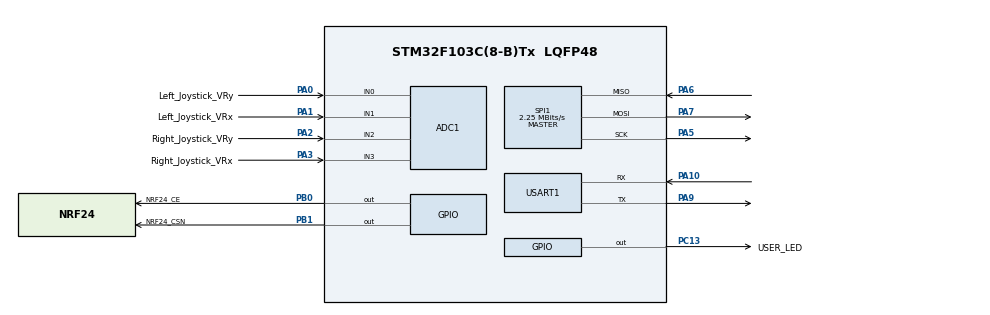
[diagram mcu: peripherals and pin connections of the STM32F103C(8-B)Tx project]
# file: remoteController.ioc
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ADC1.Channel-0\#ChannelRegularConversion=ADC_CHANNEL_0
ADC1.Channel-1\#ChannelRegularConversion=ADC_CHANNEL_1
ADC1.Channel-2\#ChannelRegularConversion=ADC_CHANNEL_2
ADC1.Channel-3\#ChannelRegularConversion=ADC_CHANNEL_3
ADC1.ContinuousConvMode=ENABLE
ADC1.NbrOfConversion=4
ADC1.NbrOfConversionFlag=1
ADC1.Rank-0\#ChannelRegularConversion=1
ADC1.Rank-1\#ChannelRegularConversion=2
ADC1.Rank-2\#ChannelRegularConversion=3
ADC1.Rank-3\#ChannelRegularConversion=4
ADC1.SamplingTime-0\#ChannelRegularConversion=ADC_SAMPLETIME_239CYCLES_5
ADC1.SamplingTime-1\#ChannelRegularConversion=ADC_SAMPLETIME_239CYCLES_5
ADC1.SamplingTime-2\#ChannelRegularConversion=ADC_SAMPLETIME_239CYCLES_5
ADC1.SamplingTime-3\#ChannelRegularConversion=ADC_SAMPLETIME_239CYCLES_5
ADC1.master=1
Dma.ADC1.0.Direction=DMA_PERIPH_TO_MEMORY
Dma.ADC1.0.Instance=DMA1_Channel1
Dma.ADC1.0.MemDataAlignment=DMA_MDATAALIGN_WORD
Dma.ADC1.0.MemInc=DMA_MINC_ENABLE
Dma.ADC1.0.Mode=DMA_CIRCULAR
Dma.ADC1.0.PeriphDataAlignment=DMA_PDATAALIGN_WORD
Dma.ADC1.0.PeriphInc=DMA_PINC_DISABLE
Dma.ADC1.0.Priority=DMA_PRIORITY_MEDIUM
Dma.Request0=ADC1
Mcu.Family=STM32F1
Mcu.Name=STM32F103C(8-B)Tx
Mcu.Package=LQFP48
NVIC.DMA1_Channel1_IRQn=true\:0\:0\:false\:false\:true\:false\:true\:true
NVIC.PriorityGroup=NVIC_PRIORITYGROUP_4
NVIC.SPI1_IRQn=true\:0\:0\:false\:false\:true\:true\:true\:true
NVIC.TIM2_IRQn=true\:0\:0\:false\:false\:true\:true\:true\:true
PA0-WKUP.GPIO_Label=Left_Joystick_VRy
PA0-WKUP.Signal=ADCx_IN0
PA1.GPIO_Label=Left_Joystick_VRx
PA1.Signal=ADCx_IN1
PA10.Mode=Asynchronous
PA10.Signal=USART1_RX
PA13.Mode=Serial_Wire
PA13.Signal=SYS_JTMS-SWDIO
PA14.Mode=Serial_Wire
PA14.Signal=SYS_JTCK-SWCLK
PA2.GPIO_Label=Right_Joystick_VRy
PA2.Signal=ADCx_IN2
PA3.GPIO_Label=Right_Joystick_VRx
PA3.Signal=ADCx_IN3
PA5.Mode=Full_Duplex_Master
PA5.Signal=SPI1_SCK
PA6.Mode=Full_Duplex_Master
PA6.Signal=SPI1_MISO
PA7.Mode=Full_Duplex_Master
PA7.Signal=SPI1_MOSI
PA9.Mode=Asynchronous
PA9.Signal=USART1_TX
PB0.GPIO_Label=NRF24_CE
PB0.GPIO_Speed=GPIO_SPEED_FREQ_HIGH
PB0.Signal=GPIO_Output
PB1.GPIO_Label=NRF24_CSN
PB1.GPIO_Speed=GPIO_SPEED_FREQ_HIGH
PB1.Signal=GPIO_Output
PC13-TAMPER-RTC.GPIO_Label=USER_LED
PC13-TAMPER-RTC.GPIO_PuPd=GPIO_PULLDOWN
PC13-TAMPER-RTC.GPIO_Speed=GPIO_SPEED_FREQ_MEDIUM
PC13-TAMPER-RTC.Signal=GPIO_Output
PD0-OSC_IN.Mode=HSE-External-Oscillator
PD0-OSC_IN.Signal=RCC_OSC_IN
PD1-OSC_OUT.Mode=HSE-External-Oscillator
PD1-OSC_OUT.Signal=RCC_OSC_OUT
ProjectManager.HeapSize=0x200
ProjectManager.StackSize=0x400
ProjectManager.TargetToolchain=STM32CubeIDE
RCC.ADCPresc=RCC_ADCPCLK2_DIV8
RCC.AHBFreq_Value=72000000
RCC.APB1CLKDivider=RCC_HCLK_DIV2
RCC.APB1Freq_Value=36000000
RCC.APB1TimFreq_Value=72000000
RCC.APB2Freq_Value=72000000
RCC.APB2TimFreq_Value=72000000
RCC.HCLKFreq_Value=72000000
RCC.PLLMUL=RCC_PLL_MUL9
RCC.PLLSourceVirtual=RCC_PLLSOURCE_HSE
RCC.SYSCLKFreq_VALUE=72000000
RCC.SYSCLKSource=RCC_SYSCLKSOURCE_PLLCLK
RCC.USBFreq_Value=72000000
SH.ADCx_IN0.0=ADC1_IN0,IN0
SH.ADCx_IN1.0=ADC1_IN1,IN1
SH.ADCx_IN2.0=ADC1_IN2,IN2
SH.ADCx_IN3.0=ADC1_IN3,IN3
SPI1.BaudRatePrescaler=SPI_BAUDRATEPRESCALER_32
SPI1.CalculateBaudRate=2.25 MBits/s
SPI1.Direction=SPI_DIRECTION_2LINES
SPI1.Mode=SPI_MODE_MASTER
SPI1.VirtualType=VM_MASTER
TIM1.Prescaler=72-1
TIM2.Period=999
TIM2.Prescaler=71
USART1.VirtualMode=VM_ASYNC
VP_TIM1_VS_ClockSourceINT.Mode=Internal
VP_TIM2_VS_ClockSourceINT.Mode=Internal
board=custom

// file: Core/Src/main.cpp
/* USER CODE BEGIN Header */
/**
  ******************************************************************************
  * @file           : main.c
  * @brief          : Main program body
  ******************************************************************************
  * @attention
  *
  * Copyright (c) 2025 STMicroelectronics.
  * All rights reserved.
  *
  * This software is licensed under terms that can be found in the LICENSE file
  * in the root directory of this software component.
  * If no LICENSE file comes with this software, it is provided AS-IS.
  *
  ******************************************************************************
  */
/* USER CODE END Header */
#include "main.h"
#include "adc.h"
#include "dma.h"
#include "spi.h"
#include "tim.h"
#include "usart.h"
#include "gpio.h"

/* USER CODE BEGIN Includes */
#include "config.h"
#include "global.h"
#include <stdio.h>
#include <string.h>
#include "softTimer.h"
#include "nrflink.h"
/* USER CODE END Includes */

/* USER CODE BEGIN PD */
uint32_t data[4];
softwareTimer timer1;

/* USER CODE END PD */

/* USER CODE BEGIN PV */
//uint8_t TxData[] = "Hello World\r\n";

uint8_t TxData[32] = {0};
/* USER CODE END PV */

void SystemClock_Config(void);

int main(void)
{

  /* MCU Configuration--------------------------------------------------------*/

  /* Reset of all peripherals, Initializes the Flash interface and the Systick. */
  HAL_Init();

  /* Configure the system clock */
  SystemClock_Config();

  /* Initialize all configured peripherals */
  MX_GPIO_Init();
  MX_DMA_Init();
  MX_ADC1_Init();
  MX_USART1_UART_Init();
  MX_SPI1_Init();
  MX_TIM2_Init();
  MX_TIM1_Init();
  /* USER CODE BEGIN 2 */
  HAL_ADC_Start_DMA(&hadc1, gu32a_adc_val, ADC_CHANNEL_NUMBERS);
  HAL_TIM_Base_Start_IT(&htim2);
  HAL_TIM_Base_Start(&htim1);  // start the Timer1

  timer1.start(100,true);

  pnrflink = new nrflink;
  TxData[0] = 0x55;
  TxData[1] = 0xAA;
  TxData[2] = 0x07;

  U8 throttle = 0;
  U8 steer = 0;

  memcpy((uint8_t*)&TxData[3],(uint8_t*)&throttle,1);
  memcpy((uint8_t*)&TxData[4],(uint8_t*)&steer,1);

  /* USER CODE END 2 */

  /* Infinite loop */
  while (1)
  {

    /* USER CODE BEGIN 3 */

    if (timer1.is_fired())
    {
        NRF24_Transmit(TxData);
        //memcpy((uint8_t*)&TxData[4],(uint8_t*)&steer,1);
       //printf("ADC IN[1] = %ld IN[2] = %ld IN[3] = %ld IN[4] = %ld \r\n",gu32a_adc_val[0],gu32a_adc_val[1],gu32a_adc_val[2],gu32a_adc_val[3]);
    }

  }
  /* USER CODE END 3 */
}

void SystemClock_Config(void)
{
  RCC_OscInitTypeDef RCC_OscInitStruct = {0};
  RCC_ClkInitTypeDef RCC_ClkInitStruct = {0};
  RCC_PeriphCLKInitTypeDef PeriphClkInit = {0};

  /** Initializes the RCC Oscillators according to the specified parameters
  * in the RCC_OscInitTypeDef structure.
  */
  RCC_OscInitStruct.OscillatorType = RCC_OSCILLATORTYPE_HSE;
  RCC_OscInitStruct.HSEState = RCC_HSE_ON;
  RCC_OscInitStruct.HSEPredivValue = RCC_HSE_PREDIV_DIV1;
  RCC_OscInitStruct.HSIState = RCC_HSI_ON;
  RCC_OscInitStruct.PLL.PLLState = RCC_PLL_ON;
  RCC_OscInitStruct.PLL.PLLSource = RCC_PLLSOURCE_HSE;
  RCC_OscInitStruct.PLL.PLLMUL = RCC_PLL_MUL9;
  if (HAL_RCC_OscConfig(&RCC_OscInitStruct) != HAL_OK)
  {
    Error_Handler();
  }

  /** Initializes the CPU, AHB and APB buses clocks
  */
  RCC_ClkInitStruct.ClockType = RCC_CLOCKTYPE_HCLK|RCC_CLOCKTYPE_SYSCLK
                              |RCC_CLOCKTYPE_PCLK1|RCC_CLOCKTYPE_PCLK2;
  RCC_ClkInitStruct.SYSCLKSource = RCC_SYSCLKSOURCE_PLLCLK;
  RCC_ClkInitStruct.AHBCLKDivider = RCC_SYSCLK_DIV1;
  RCC_ClkInitStruct.APB1CLKDivider = RCC_HCLK_DIV2;
  RCC_ClkInitStruct.APB2CLKDivider = RCC_HCLK_DIV4;

  if (HAL_RCC_ClockConfig(&RCC_ClkInitStruct, FLASH_LATENCY_2) != HAL_OK)
  {
    Error_Handler();
  }
  PeriphClkInit.PeriphClockSelection = RCC_PERIPHCLK_ADC;
  PeriphClkInit.AdcClockSelection = RCC_ADCPCLK2_DIV2;
  if (HAL_RCCEx_PeriphCLKConfig(&PeriphClkInit) != HAL_OK)
  {
    Error_Handler();
  }
}

/* USER CODE BEGIN 4 */
void HAL_TIM_PeriodElapsedCallback(TIM_HandleTypeDef* htim)
{
	if(htim->Instance == htim2.Instance)
	{
		  timer1.timer();
	}
}
/* USER CODE END 4 */

void Error_Handler(void)
{
  __disable_irq();
  while (1)
  {
  }
}
